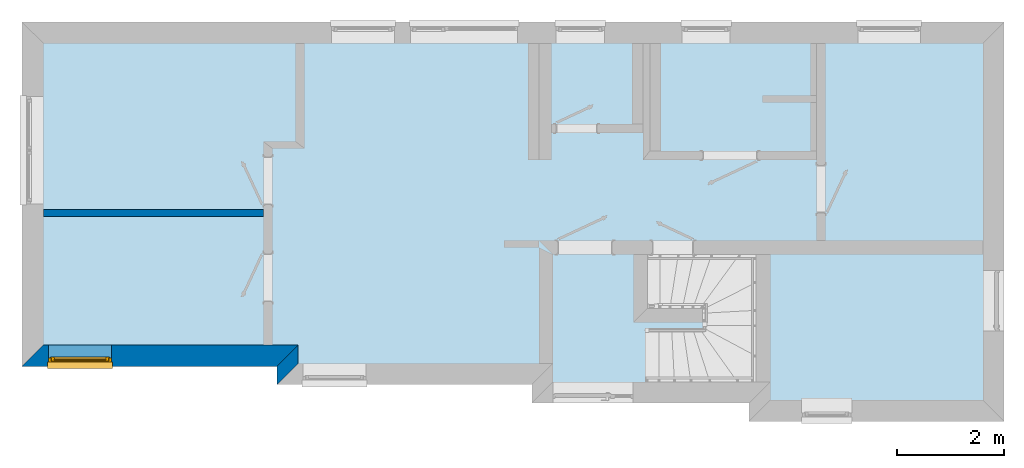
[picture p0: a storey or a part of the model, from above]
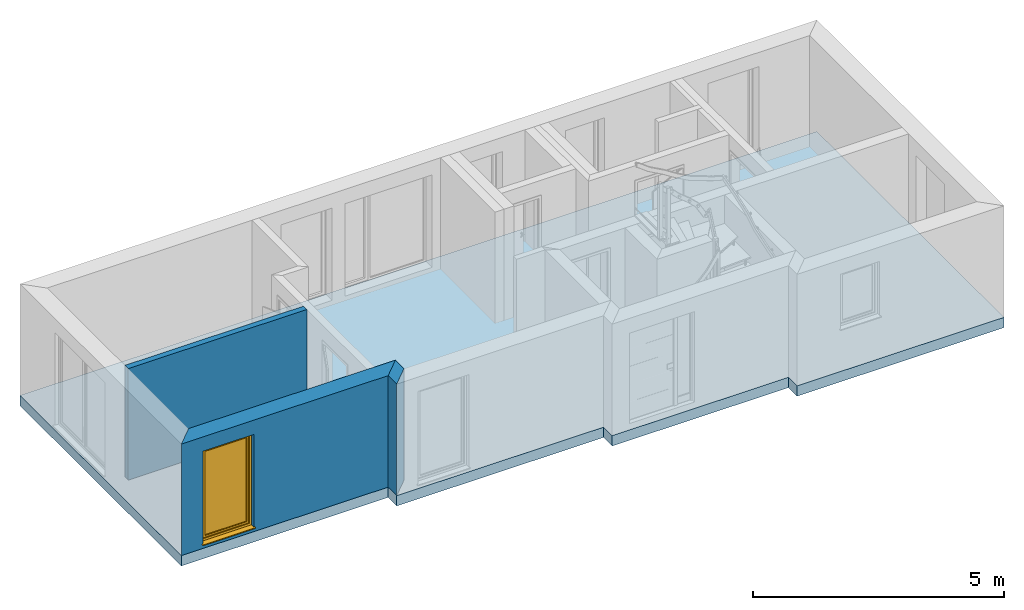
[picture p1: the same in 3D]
Properties of the parts of a building model (IFC2X3)

# File
Description: ViewDefinition[CoordinationView]
File name: C:\Users\Sylvia Büdenbender\Documents\derHausblogger Shop\Mehrfamilienhäuser\Mehrfamilienhaus_242.16m2\dwg-und-ifc-Dateien\Mehrfamilienhaus_242.16m2.ifc
Time: 2026-02-22T17:17:24
Made in: Vi Plan 27.0

# IfcBuildingStorey (3)
In: ?
Name | Description | Elevation (mm)
Erdgeschoß | Erdgeschoß | 0
Obergeschoß 1 | Obergeschoß 1 | 2969
Dachgeschoß | Dachgeschoß | 5938

# IfcDoor (23)
Name | In | Description | OverallHeight (mm) | OverallWidth (mm)
HT01 | Erdgeschoß | Haustür | 2194 | 1120
HT02 | Erdgeschoß | Haustür | 2194 | 1150
IT02 | Erdgeschoß | Innentür | 2135 | 760
IT01 | Erdgeschoß | Innentür | 2135 | 1010
IT03 | Erdgeschoß | Innentür | 2135 | 885
IT04 | Erdgeschoß | Innentür | 2135 | 1010
IT05 | Erdgeschoß | Innentür | 2135 | 760
IT07 | Erdgeschoß | Innentür | 2135 | 885
IT06 | Erdgeschoß | Innentür | 2135 | 885
IT08 | Obergeschoß 1 | Innentür | 2135 | 1010
IT09 | Obergeschoß 1 | Innentür | 2135 | 885
IT10 | Obergeschoß 1 | Innentür | 2135 | 1010
IT11 | Obergeschoß 1 | Innentür | 2135 | 885
IT12 | Obergeschoß 1 | Innentür | 2135 | 760
IT13 | Obergeschoß 1 | Innentür | 2135 | 760
IT14 | Obergeschoß 1 | Innentür | 2135 | 885
IT15 | Dachgeschoß | Innentür | 2135 | 1010
IT16 | Dachgeschoß | Innentür | 2135 | 885
IT17 | Dachgeschoß | Innentür | 2135 | 1010
IT18 | Dachgeschoß | Innentür | 2135 | 885
IT19 | Dachgeschoß | Innentür | 2135 | 760
IT20 | Dachgeschoß | Innentür | 2135 | 760
IT21 | Dachgeschoß | Innentür | 2135 | 885

# IfcOpeningElement (64)
Name | In
AW-01/FE01 | Erdgeschoß | Vi_OpeningInformation - PanelLeftRepType: Tür; PanelLeftWidth: 0
AW-01/FE02 | Erdgeschoß | Vi_OpeningInformation - PanelLeftRepType: Fenster; PanelLeftWidth: 1330; PanelRightRepType: Tür; PanelRightWidth: 0
AW-01/FE03 | Erdgeschoß | Vi_OpeningInformation - PanelLeftRepType: Tür; PanelLeftWidth: 0
AW-01/FE04 | Erdgeschoß | Vi_OpeningInformation - PanelLeftRepType: Tür; PanelLeftWidth: 0
AW-01/FE05 | Erdgeschoß | Vi_OpeningInformation - PanelLeftRepType: Tür; PanelLeftWidth: 0
AW-02/HT01 | Erdgeschoß
AW-03/FE06 | Erdgeschoß | Vi_OpeningInformation - PanelLeftRepType: Fenster; PanelLeftWidth: 0
AW-05/HT02 | Erdgeschoß
AW-07/FE07 | Erdgeschoß | Vi_OpeningInformation - PanelLeftRepType: Tür; PanelLeftWidth: 0
AW-09/FE08 | Erdgeschoß | Vi_OpeningInformation - PanelLeftRepType: Tür; PanelLeftWidth: 0
AW-10/FE09 | Erdgeschoß | Vi_OpeningInformation - PanelLeftRepType: Tür; PanelLeftWidth: 0; PanelRightRepType: Tür; PanelRightWidth: 0; PanelLeftSashType: Bedarfsflügel; PanelRightSashType: Gangflügel
IW-03/IT02 | Erdgeschoß
IW-03/IT01 | Erdgeschoß
IW-04/IT03 | Erdgeschoß
IW-05/IT04 | Erdgeschoß
IW-10/IT05 | Erdgeschoß
IW-13/IT07 | Erdgeschoß
IW-13/IT06 | Erdgeschoß
DE/Treppe01 | Obergeschoß 1
AW-11/FE11 | Obergeschoß 1 | Vi_OpeningInformation - PanelBottomRepType: Fenster; PanelBottomWidth: 0; PanelTopRepType: Fenster; PanelTopWidth: 0
AW-11/FE13 | Obergeschoß 1 | Vi_OpeningInformation - PanelBottomRepType: Fenster; PanelBottomWidth: 0; PanelTopRepType: Fenster; PanelTopWidth: 0
AW-11/FE14 | Obergeschoß 1 | Vi_OpeningInformation - PanelBottomRepType: Fenster; PanelBottomWidth: 0; PanelTopRepType: Fenster; PanelTopWidth: 0
AW-11/FE15 | Obergeschoß 1 | Vi_OpeningInformation - PanelLeftRepType: Fenster; PanelLeftWidth: 1330; PanelRightRepType: Fenster; PanelRightWidth: 0; PanelLeftSashType: Bedarfsflügel; PanelRightSashType: Gangflügel; PanelBottomRepType: Fenster; PanelBottomWidth: 0
AW-11/FE12 | Obergeschoß 1 | Vi_OpeningInformation - PanelBottomRepType: Fenster; PanelBottomWidth: 0; PanelTopRepType: Fenster; PanelTopWidth: 0
AW-11/FE10 | Obergeschoß 1 | Vi_OpeningInformation - PanelBottomRepType: Fenster; PanelBottomWidth: 0; PanelTopRepType: Fenster; PanelTopWidth: 0
AW-12/FE16 | Obergeschoß 1 | Vi_OpeningInformation - PanelLeftRepType: Fenster; PanelLeftWidth: 1330; PanelRightRepType: Fenster; PanelRightWidth: 0; PanelLeftSashType: Bedarfsflügel; PanelRightSashType: Gangflügel; PanelBottomRepType: Fenster; PanelBottomWidth: 0
AW-15/FE17 | Obergeschoß 1 | Vi_OpeningInformation - PanelBottomRepType: Fenster; PanelBottomWidth: 0; PanelTopRepType: Fenster; PanelTopWidth: 0
AW-17/FE18 | Obergeschoß 1 | Vi_OpeningInformation - PanelLeftRepType: Fenster; PanelLeftWidth: 0; PanelRightRepType: Fenster; PanelRightWidth: 1330; PanelLeftSashType: Gangflügel; PanelRightSashType: Bedarfsflügel; PanelBottomRepType: Fenster; PanelBottomWidth: 0
AW-20/FE19 | Obergeschoß 1 | Vi_OpeningInformation - PanelBottomRepType: Fenster; PanelBottomWidth: 0; PanelTopRepType: Fenster; PanelTopWidth: 0
IW-22/IT08 | Obergeschoß 1
IW-24/IT09 | Obergeschoß 1
IW-25/IT10 | Obergeschoß 1
IW-26/IT11 | Obergeschoß 1
IW-27/IT12 | Obergeschoß 1
IW-30/IT13 | Obergeschoß 1
IW-34/IT14 | Obergeschoß 1
DE/Treppe02 | Dachgeschoß
AW-22/FE20 | Dachgeschoß | Vi_OpeningInformation - PanelBottomRepType: Fenster; PanelBottomWidth: 0; PanelTopRepType: Fenster; PanelTopWidth: 0
AW-30/FE21 | Dachgeschoß | Vi_OpeningInformation - PanelBottomRepType: Fenster; PanelBottomWidth: 0; PanelTopRepType: Fenster; PanelTopWidth: 0
IW-37/IT15 | Dachgeschoß
IW-39/IT16 | Dachgeschoß
IW-40/IT17 | Dachgeschoß
IW-41/IT18 | Dachgeschoß
IW-42/IT19 | Dachgeschoß
IW-45/IT20 | Dachgeschoß
IW-49/IT21 | Dachgeschoß
DAFL_Rafter/DF01 | Dachgeschoß
DAFL_Tile/DF01 | Dachgeschoß
DAFL_Rafter/DF02 | Dachgeschoß
DAFL_Tile/DF02 | Dachgeschoß
DAFL_Rafter/DF03 | Dachgeschoß
DAFL_Tile/DF03 | Dachgeschoß
DAFL_Rafter/DF04 | Dachgeschoß
DAFL_Rafter/DF05 | Dachgeschoß
DAFL_Tile/DF04 | Dachgeschoß
DAFL_Tile/DF05 | Dachgeschoß
DAFL_Rafter/DF06 | Dachgeschoß
DAFL_Rafter/DF07 | Dachgeschoß
DAFL_Tile/DF06 | Dachgeschoß
DAFL_Tile/DF07 | Dachgeschoß
DAFL_Rafter/DF08 | Dachgeschoß
DAFL_Tile/DF08 | Dachgeschoß
DAFL_Rafter/DF09 | Dachgeschoß
DAFL_Tile/DF09 | Dachgeschoß

# IfcRoof (4)
In: Dachgeschoß
Description: Pfetten-/Sparrendach
Name
Dach01
Dach02
Dach03
Dach04

# IfcSlab (19)
Name | In | Description | PredefinedType
DE | Erdgeschoß | Erdgeschoß | BASESLAB
DE | Obergeschoß 1 | Obergeschoß 1 | FLOOR
DE | Dachgeschoß | Dachgeschoß | FLOOR
8 x DAFL_Rafter | Dachgeschoß | Dachfläche - Sparren | ROOF
8 x DAFL_Tile | Dachgeschoß | Dachfläche - Eindeckung | ROOF

# IfcStair (2)
Description: Treppe
Name | In
Treppe01 | Erdgeschoß
Treppe02 | Obergeschoß 1

# IfcWall (81)
Pset_WallCommon - AcousticRating: ?; Combustible: no; Compartmentation: no; FireRating: ?; Reference: ?; SurfaceSpreadOfFlame: ?; ThermalTransmittance: 0
Name | In | Material | ExtendToStructure | IsExternal | LoadBearing
AW-01 | Erdgeschoß | Material_AW 395 mm | yes | yes | yes
AW-02 | Erdgeschoß | Material_AW 395 mm | yes | yes | yes
AW-03 | Erdgeschoß | Material_AW 395 mm | yes | yes | yes
AW-04 | Erdgeschoß | Material_AW 395 mm | yes | yes | yes
AW-05 | Erdgeschoß | Material_AW 395 mm | yes | yes | yes
AW-06 | Erdgeschoß | Material_AW 395 mm | yes | yes | yes
AW-07 | Erdgeschoß | Material_AW 395 mm | yes | yes | yes
AW-08 | Erdgeschoß | Material_AW 395 mm | yes | yes | yes
AW-09 | Erdgeschoß | Material_AW 395 mm | yes | yes | yes
AW-10 | Erdgeschoß | Material_AW 395 mm | yes | yes | yes
IW-01 | Erdgeschoß | Material_IW 264 mm | no | no | yes
IW-02 | Erdgeschoß | Material_IW 264 mm | no | no | yes
IW-03 | Erdgeschoß | Material_IW 264 mm | no | no | yes
IW-04 | Erdgeschoß | Material_IW 172 mm | no | no | yes
IW-05 | Erdgeschoß | Material_IW 172 mm | no | no | yes
IW-06 | Erdgeschoß | Material_IW 232 mm | no | no | yes
IW-07 | Erdgeschoß | Material_IW 132 mm | no | no | no
IW-08 | Erdgeschoß | Material_IW 206 mm | no | no | no
IW-09 | Erdgeschoß | Material_IW 132 mm | no | no | no
IW-10 | Erdgeschoß | Material_IW 172 mm | no | no | yes
IW-11 | Erdgeschoß | Material_IW 206 mm | no | no | no
IW-12 | Erdgeschoß | Material_IW 106 mm | no | no | no
IW-13 | Erdgeschoß | Material_IW 172 mm | no | no | yes
IW-14 | Erdgeschoß | Material_IW 132 mm | no | no | no
IW-15 | Erdgeschoß | Material_IW 132 mm | no | no | no
IW-16 | Erdgeschoß | Material_IW 172 mm | no | no | yes
IW-17 | Erdgeschoß | Material_IW 132 mm | no | no | no
IW-18 | Erdgeschoß | Material_IW 106 mm | no | no | no
IW-19 | Erdgeschoß | Material_IW 264 mm | no | no | yes
IW-20 | Erdgeschoß | Material_IW 264 mm | no | no | yes
IW-21 | Erdgeschoß | Material_IW 206 mm | no | no | no
AW-11 | Obergeschoß 1 | Material_AW 395 mm | yes | yes | yes
AW-12 | Obergeschoß 1 | Material_AW 395 mm | yes | yes | yes
AW-13 | Obergeschoß 1 | Material_AW 395 mm | yes | yes | yes
AW-14 | Obergeschoß 1 | Material_AW 395 mm | yes | yes | yes
AW-15 | Obergeschoß 1 | Material_AW 395 mm | yes | yes | yes
AW-16 | Obergeschoß 1 | Material_AW 395 mm | yes | yes | yes
AW-17 | Obergeschoß 1 | Material_AW 395 mm | yes | yes | yes
AW-18 | Obergeschoß 1 | Material_AW 395 mm | yes | yes | yes
AW-19 | Obergeschoß 1 | Material_AW 395 mm | yes | yes | yes
AW-20 | Obergeschoß 1 | Material_AW 395 mm | yes | yes | yes
IW-22 | Obergeschoß 1 | Material_IW 264 mm | no | no | yes
IW-23 | Obergeschoß 1 | Material_IW 264 mm | no | no | yes
IW-24 | Obergeschoß 1 | Material_IW 132 mm | no | no | no
IW-25 | Obergeschoß 1 | Material_IW 264 mm | no | no | yes
IW-26 | Obergeschoß 1 | Material_IW 172 mm | no | no | yes
IW-27 | Obergeschoß 1 | Material_IW 172 mm | no | no | yes
IW-28 | Obergeschoß 1 | Material_IW 206 mm | no | no | no
IW-29 | Obergeschoß 1 | Material_IW 172 mm | no | no | yes
IW-30 | Obergeschoß 1 | Material_IW 172 mm | no | no | yes
IW-31 | Obergeschoß 1 | Material_IW 172 mm | no | no | yes
IW-32 | Obergeschoß 1 | Material_IW 206 mm | no | no | no
IW-33 | Obergeschoß 1 | Material_IW 172 mm | no | no | yes
IW-34 | Obergeschoß 1 | Material_IW 172 mm | no | no | yes
IW-35 | Obergeschoß 1 | Material_IW 132 mm | no | no | no
IW-36 | Obergeschoß 1 | Material_IW 132 mm | no | no | no
AW-21 | Dachgeschoß | Material_AW 395 mm | yes | yes | yes
AW-22 | Dachgeschoß | Material_AW 395 mm | yes | yes | yes
AW-23 | Dachgeschoß | Material_AW 395 mm | yes | yes | yes
AW-24 | Dachgeschoß | Material_AW 395 mm | yes | yes | yes
AW-25 | Dachgeschoß | Material_AW 395 mm | yes | yes | yes
AW-26 | Dachgeschoß | Material_AW 395 mm | yes | yes | yes
AW-27 | Dachgeschoß | Material_AW 395 mm | yes | yes | yes
AW-28 | Dachgeschoß | Material_AW 395 mm | yes | yes | yes
AW-29 | Dachgeschoß | Material_AW 395 mm | yes | yes | yes
AW-30 | Dachgeschoß | Material_AW 395 mm | yes | yes | yes
IW-37 | Dachgeschoß | Material_IW 264 mm | yes | no | yes
IW-38 | Dachgeschoß | Material_IW 264 mm | yes | no | yes
IW-39 | Dachgeschoß | Material_IW 132 mm | yes | no | no
IW-40 | Dachgeschoß | Material_IW 264 mm | yes | no | yes
IW-41 | Dachgeschoß | Material_IW 172 mm | yes | no | yes
IW-42 | Dachgeschoß | Material_IW 172 mm | yes | no | yes
IW-43 | Dachgeschoß | Material_IW 206 mm | yes | no | no
IW-44 | Dachgeschoß | Material_IW 172 mm | yes | no | yes
IW-45 | Dachgeschoß | Material_IW 172 mm | yes | no | yes
IW-46 | Dachgeschoß | Material_IW 172 mm | yes | no | yes
IW-47 | Dachgeschoß | Material_IW 206 mm | yes | no | no
IW-48 | Dachgeschoß | Material_IW 172 mm | yes | no | yes
IW-49 | Dachgeschoß | Material_IW 172 mm | yes | no | yes
IW-50 | Dachgeschoß | Material_IW 132 mm | yes | no | no
IW-51 | Dachgeschoß | Material_IW 132 mm | yes | no | no

# IfcWindow (31)
In: Dachgeschoß
Name | Description | OverallHeight (mm) | OverallWidth (mm)
DF01 | Dachfenster | 1400 | 940
DF02 | Dachfenster | 1400 | 940
22 x SO | Solaranlage | 1730 | 1130
DF03 | Dachfenster | 1400 | 940
DF04 | Dachfenster | 1400 | 940
DF05 | Dachfenster | 1400 | 940
DF06 | Dachfenster | 1400 | 940
DF07 | Dachfenster | 1400 | 940
DF08 | Dachfenster | 1400 | 940
DF09 | Dachfenster | 1400 | 940

# IfcWindow: FE01
In: Erdgeschoß
Type - Description: Terrassentür[0][1][0]; OperationType: SINGLE_PANEL; ParameterTakesPrecedence: yes; Sizeable: no
Type - FE01_Panel#000 - Description: Terrassentürpanel; OperationType: TILTANDTURNRIGHTHAND; PanelPosition: LEFT
OverallHeight: 2244 mm; OverallWidth: 1170 mm
Vi_OpeningInformation - PanelLeftRepType: Tür; PanelLeftWidth: 0

# IfcWindow: FE02
In: Erdgeschoß
Type - Description: Terrassentür[4][1][1]; OperationType: DOUBLE_PANEL_VERTICAL; ParameterTakesPrecedence: no; Sizeable: no
Type - FE02_Panel#000 - Description: Terrassentürpanel; OperationType: FIXEDCASEMENT; PanelPosition: LEFT
Type - FE02_Panel#001 - Description: Terrassentürpanel; OperationType: TILTANDTURNRIGHTHAND; PanelPosition: RIGHT
OverallHeight: 2244 mm; OverallWidth: 2000 mm
Vi_OpeningInformation - PanelLeftRepType: Fenster; PanelLeftWidth: 1330; PanelRightRepType: Tür; PanelRightWidth: 0

# IfcWindow: FE03
In: Erdgeschoß
Type - Description: Terrassentür[0][1][0]; OperationType: SINGLE_PANEL; ParameterTakesPrecedence: yes; Sizeable: no
Type - FE03_Panel#000 - Description: Terrassentürpanel; OperationType: TILTANDTURNRIGHTHAND; PanelPosition: LEFT
OverallHeight: 2244 mm; OverallWidth: 900 mm
Vi_OpeningInformation - PanelLeftRepType: Tür; PanelLeftWidth: 0

# IfcWindow: FE04
In: Erdgeschoß
Type - Description: Terrassentür[0][0][0]; OperationType: SINGLE_PANEL; ParameterTakesPrecedence: yes; Sizeable: no
Type - FE04_Panel#000 - Description: Terrassentürpanel; OperationType: TILTANDTURNLEFTHAND; PanelPosition: LEFT
OverallHeight: 2244 mm; OverallWidth: 900 mm
Vi_OpeningInformation - PanelLeftRepType: Tür; PanelLeftWidth: 0

# IfcWindow: FE05
In: Erdgeschoß
Type - Description: Terrassentür[0][1][0]; OperationType: SINGLE_PANEL; ParameterTakesPrecedence: yes; Sizeable: no
Type - FE05_Panel#000 - Description: Terrassentürpanel; OperationType: TILTANDTURNRIGHTHAND; PanelPosition: LEFT
OverallHeight: 2244 mm; OverallWidth: 1170 mm
Vi_OpeningInformation - PanelLeftRepType: Tür; PanelLeftWidth: 0

# IfcWindow: FE06
In: Erdgeschoß
Type - Description: Fenster[0][1][0]; OperationType: SINGLE_PANEL; ParameterTakesPrecedence: yes; Sizeable: no
Type - FE06_Panel#000 - Description: Fensterpanel; OperationType: TILTANDTURNLEFTHAND; PanelPosition: LEFT
OverallHeight: 1320 mm; OverallWidth: 900 mm
Vi_OpeningInformation - PanelLeftRepType: Fenster; PanelLeftWidth: 0

# IfcWindow: FE07
In: Erdgeschoß
Type - Description: Terrassentür[0][0][0]; OperationType: SINGLE_PANEL; ParameterTakesPrecedence: yes; Sizeable: no
Type - FE07_Panel#000 - Description: Terrassentürpanel; OperationType: TILTANDTURNLEFTHAND; PanelPosition: LEFT
OverallHeight: 2244 mm; OverallWidth: 1170 mm
Vi_OpeningInformation - PanelLeftRepType: Tür; PanelLeftWidth: 0

# IfcWindow: FE08
In: Erdgeschoß
Type - Description: Terrassentür[0][0][0]; OperationType: SINGLE_PANEL; ParameterTakesPrecedence: yes; Sizeable: no
Type - FE08_Panel#000 - Description: Terrassentürpanel; OperationType: TILTANDTURNLEFTHAND; PanelPosition: LEFT
OverallHeight: 2244 mm; OverallWidth: 1170 mm
Vi_OpeningInformation - PanelLeftRepType: Tür; PanelLeftWidth: 0

# IfcWindow: FE09
In: Erdgeschoß
Type - Description: Terrassentür[1][1][0]; OperationType: DOUBLE_PANEL_VERTICAL; ParameterTakesPrecedence: yes; Sizeable: no
Type - FE09_Panel#000 - Description: Terrassentürpanel; OperationType: TILTANDTURNLEFTHAND; PanelPosition: LEFT
Type - FE09_Panel#001 - Description: Terrassentürpanel; OperationType: TILTANDTURNRIGHTHAND; PanelPosition: RIGHT
OverallHeight: 2244 mm; OverallWidth: 2000 mm
Vi_OpeningInformation - PanelLeftRepType: Tür; PanelLeftSashType: Bedarfsflügel; PanelLeftWidth: 0; PanelRightRepType: Tür; PanelRightSashType: Gangflügel; PanelRightWidth: 0

# IfcWindow: FE10
In: Obergeschoß 1
Type - Description: Terrassentür[60][0][0]; OperationType: DOUBLE_PANEL_HORIZONTAL; ParameterTakesPrecedence: yes; Sizeable: no
Type - FE10_Panel#000 - Description: Terrassentürpanel; OperationType: TILTANDTURNLEFTHAND; PanelPosition: TOP
Type - FE10_Panel#001 - Description: Terrassentürpanel; OperationType: FIXEDCASEMENT; PanelPosition: BOTTOM
OverallHeight: 2244 mm; OverallWidth: 1170 mm
Vi_OpeningInformation - PanelBottomRepType: Fenster; PanelBottomWidth: 0; PanelTopRepType: Fenster; PanelTopWidth: 0

# IfcWindow: FE11
In: Obergeschoß 1
Type - Description: Terrassentür[60][1][0]; OperationType: DOUBLE_PANEL_HORIZONTAL; ParameterTakesPrecedence: yes; Sizeable: no
Type - FE11_Panel#000 - Description: Terrassentürpanel; OperationType: TILTANDTURNRIGHTHAND; PanelPosition: TOP
Type - FE11_Panel#001 - Description: Terrassentürpanel; OperationType: FIXEDCASEMENT; PanelPosition: BOTTOM
OverallHeight: 2244 mm; OverallWidth: 1170 mm
Vi_OpeningInformation - PanelBottomRepType: Fenster; PanelBottomWidth: 0; PanelTopRepType: Fenster; PanelTopWidth: 0

# IfcWindow: FE12
In: Obergeschoß 1
Type - Description: Terrassentür[60][1][0]; OperationType: DOUBLE_PANEL_HORIZONTAL; ParameterTakesPrecedence: yes; Sizeable: no
Type - FE12_Panel#000 - Description: Terrassentürpanel; OperationType: TILTANDTURNRIGHTHAND; PanelPosition: TOP
Type - FE12_Panel#001 - Description: Terrassentürpanel; OperationType: FIXEDCASEMENT; PanelPosition: BOTTOM
OverallHeight: 2244 mm; OverallWidth: 900 mm
Vi_OpeningInformation - PanelBottomRepType: Fenster; PanelBottomWidth: 0; PanelTopRepType: Fenster; PanelTopWidth: 0

# IfcWindow: FE13
In: Obergeschoß 1
Type - Description: Terrassentür[60][0][0]; OperationType: DOUBLE_PANEL_HORIZONTAL; ParameterTakesPrecedence: yes; Sizeable: no
Type - FE13_Panel#000 - Description: Terrassentürpanel; OperationType: TILTANDTURNLEFTHAND; PanelPosition: TOP
Type - FE13_Panel#001 - Description: Terrassentürpanel; OperationType: FIXEDCASEMENT; PanelPosition: BOTTOM
OverallHeight: 2244 mm; OverallWidth: 900 mm
Vi_OpeningInformation - PanelBottomRepType: Fenster; PanelBottomWidth: 0; PanelTopRepType: Fenster; PanelTopWidth: 0

# IfcWindow: FE14
In: Obergeschoß 1
Type - Description: Terrassentür[60][1][0]; OperationType: DOUBLE_PANEL_HORIZONTAL; ParameterTakesPrecedence: yes; Sizeable: no
Type - FE14_Panel#000 - Description: Terrassentürpanel; OperationType: TILTANDTURNRIGHTHAND; PanelPosition: TOP
Type - FE14_Panel#001 - Description: Terrassentürpanel; OperationType: FIXEDCASEMENT; PanelPosition: BOTTOM
OverallHeight: 2244 mm; OverallWidth: 900 mm
Vi_OpeningInformation - PanelBottomRepType: Fenster; PanelBottomWidth: 0; PanelTopRepType: Fenster; PanelTopWidth: 0

# IfcWindow: FE15
In: Obergeschoß 1
Type - Description: Terrassentür[62000][1][1]; OperationType: TRIPLE_PANEL_BOTTOM; ParameterTakesPrecedence: no; Sizeable: no
Type - FE15_Panel#000 - Description: Terrassentürpanel; OperationType: TILTANDTURNLEFTHAND; PanelPosition: LEFT
Type - FE15_Panel#001 - Description: Terrassentürpanel; OperationType: TILTANDTURNRIGHTHAND; PanelPosition: RIGHT
Type - FE15_Panel#002 - Description: Terrassentürpanel; OperationType: FIXEDCASEMENT; PanelPosition: BOTTOM
OverallHeight: 2244 mm; OverallWidth: 2000 mm
Vi_OpeningInformation - PanelBottomRepType: Fenster; PanelBottomWidth: 0; PanelLeftRepType: Fenster; PanelLeftSashType: Bedarfsflügel; PanelLeftWidth: 1330; PanelRightRepType: Fenster; PanelRightSashType: Gangflügel; PanelRightWidth: 0

# IfcWindow: FE16
In: Obergeschoß 1
Type - Description: Terrassentür[62000][1][1]; OperationType: TRIPLE_PANEL_BOTTOM; ParameterTakesPrecedence: no; Sizeable: no
Type - FE16_Panel#000 - Description: Terrassentürpanel; OperationType: TILTANDTURNLEFTHAND; PanelPosition: LEFT
Type - FE16_Panel#001 - Description: Terrassentürpanel; OperationType: TILTANDTURNRIGHTHAND; PanelPosition: RIGHT
Type - FE16_Panel#002 - Description: Terrassentürpanel; OperationType: FIXEDCASEMENT; PanelPosition: BOTTOM
OverallHeight: 2244 mm; OverallWidth: 2000 mm
Vi_OpeningInformation - PanelBottomRepType: Fenster; PanelBottomWidth: 0; PanelLeftRepType: Fenster; PanelLeftSashType: Bedarfsflügel; PanelLeftWidth: 1330; PanelRightRepType: Fenster; PanelRightSashType: Gangflügel; PanelRightWidth: 0

# IfcWindow: FE17
In: Obergeschoß 1
Type - Description: Terrassentür[60][0][0]; OperationType: DOUBLE_PANEL_HORIZONTAL; ParameterTakesPrecedence: yes; Sizeable: no
Type - FE17_Panel#000 - Description: Terrassentürpanel; OperationType: TILTANDTURNLEFTHAND; PanelPosition: TOP
Type - FE17_Panel#001 - Description: Terrassentürpanel; OperationType: FIXEDCASEMENT; PanelPosition: BOTTOM
OverallHeight: 2244 mm; OverallWidth: 1170 mm
Vi_OpeningInformation - PanelBottomRepType: Fenster; PanelBottomWidth: 0; PanelTopRepType: Fenster; PanelTopWidth: 0

# IfcWindow: FE18
In: Obergeschoß 1
Type - Description: Terrassentür[62000][0][1]; OperationType: TRIPLE_PANEL_BOTTOM; ParameterTakesPrecedence: no; Sizeable: no
Type - FE18_Panel#000 - Description: Terrassentürpanel; OperationType: TILTANDTURNLEFTHAND; PanelPosition: LEFT
Type - FE18_Panel#001 - Description: Terrassentürpanel; OperationType: TILTANDTURNRIGHTHAND; PanelPosition: RIGHT
Type - FE18_Panel#002 - Description: Terrassentürpanel; OperationType: FIXEDCASEMENT; PanelPosition: BOTTOM
OverallHeight: 2244 mm; OverallWidth: 2000 mm
Vi_OpeningInformation - PanelBottomRepType: Fenster; PanelBottomWidth: 0; PanelLeftRepType: Fenster; PanelLeftSashType: Gangflügel; PanelLeftWidth: 0; PanelRightRepType: Fenster; PanelRightSashType: Bedarfsflügel; PanelRightWidth: 1330

# IfcWindow: FE19
In: Obergeschoß 1
Type - Description: Terrassentür[60][1][0]; OperationType: DOUBLE_PANEL_HORIZONTAL; ParameterTakesPrecedence: yes; Sizeable: no
Type - FE19_Panel#000 - Description: Terrassentürpanel; OperationType: TILTANDTURNRIGHTHAND; PanelPosition: TOP
Type - FE19_Panel#001 - Description: Terrassentürpanel; OperationType: FIXEDCASEMENT; PanelPosition: BOTTOM
OverallHeight: 2244 mm; OverallWidth: 1170 mm
Vi_OpeningInformation - PanelBottomRepType: Fenster; PanelBottomWidth: 0; PanelTopRepType: Fenster; PanelTopWidth: 0

# IfcWindow: FE20
In: Dachgeschoß
Type - Description: Terrassentür[60][0][0]; OperationType: DOUBLE_PANEL_HORIZONTAL; ParameterTakesPrecedence: yes; Sizeable: no
Type - FE20_Panel#000 - Description: Terrassentürpanel; OperationType: TILTANDTURNLEFTHAND; PanelPosition: TOP
Type - FE20_Panel#001 - Description: Terrassentürpanel; OperationType: FIXEDCASEMENT; PanelPosition: BOTTOM
OverallHeight: 2244 mm; OverallWidth: 1170 mm
Vi_OpeningInformation - PanelBottomRepType: Fenster; PanelBottomWidth: 0; PanelTopRepType: Fenster; PanelTopWidth: 0

# IfcWindow: FE21
In: Dachgeschoß
Type - Description: Terrassentür[60][0][0]; OperationType: DOUBLE_PANEL_HORIZONTAL; ParameterTakesPrecedence: yes; Sizeable: no
Type - FE21_Panel#000 - Description: Terrassentürpanel; OperationType: TILTANDTURNLEFTHAND; PanelPosition: TOP
Type - FE21_Panel#001 - Description: Terrassentürpanel; OperationType: FIXEDCASEMENT; PanelPosition: BOTTOM
OverallHeight: 2244 mm; OverallWidth: 1170 mm
Vi_OpeningInformation - PanelBottomRepType: Fenster; PanelBottomWidth: 0; PanelTopRepType: Fenster; PanelTopWidth: 0
